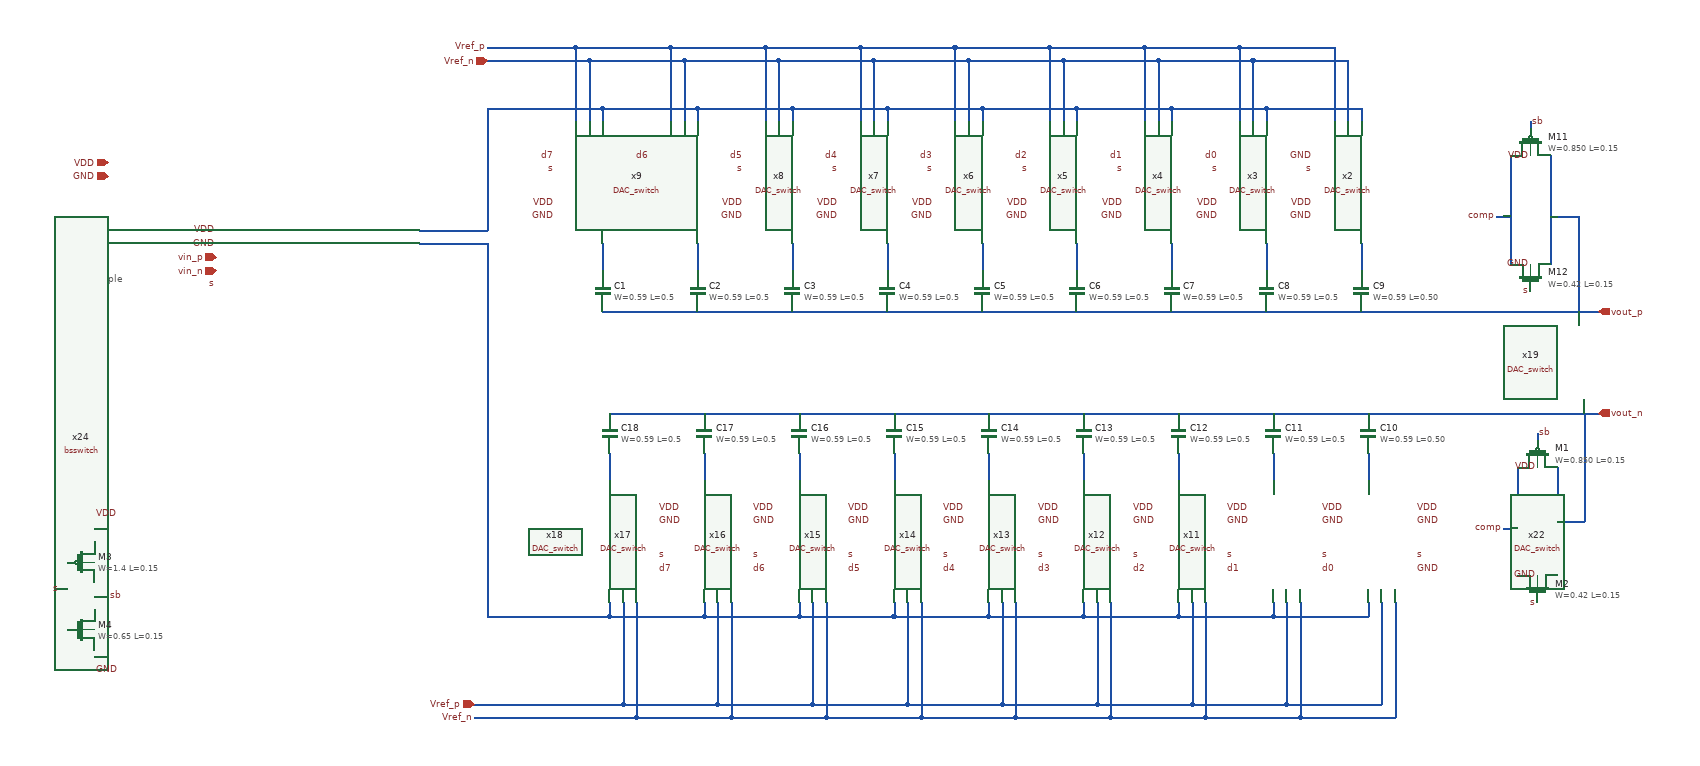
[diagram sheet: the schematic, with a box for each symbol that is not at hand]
v {xschem version=3.4.5 file_version=1.2
}
G {}
K {}
V {}
S {}
E {}
T {sample} -910 -60 0 0 0.2 0.2 {}
N -150 -300 -10 -300 {
lab=#net1}
N 830 -300 970 -300 {
lab=#net1}
N -10 -300 -10 -280 {
lab=#net1}
N 0 450 140 450 {
lab=#net2}
N 840 450 980 450 {
lab=#net2}
N -190 -390 -50 -390 {
lab=Vref_p}
N 880 600 1020 600 {
lab=Vref_n}
N -150 0 1080 0 {
lab=vout_p}
N -140 150 1160 150 {
lab=vout_n}
N 1080 0 1240 -0 {
lab=vout_p}
N 1160 150 1240 150 {
lab=vout_n}
N 1240 -0 1320 -0 {
lab=vout_p}
N 1240 150 1320 150 {
lab=vout_n}
N -420 -100 -320 -100 {
lab=#net1}
N -420 -120 -340 -120 {
lab=#net2}
N 950 -370 950 -290 {
lab=Vref_n}
N 930 -390 930 -280 {
lab=Vref_p}
N 790 -390 930 -390 {
lab=Vref_p}
N 790 -390 790 -280 {
lab=Vref_p}
N 810 -370 810 -280 {
lab=Vref_n}
N 650 -390 650 -280 {
lab=Vref_p}
N 670 -370 670 -280 {
lab=Vref_n}
N 510 -390 510 -280 {
lab=Vref_p}
N 530 -370 530 -280 {
lab=Vref_n}
N 370 -390 370 -280 {
lab=Vref_p}
N 390 -370 390 -280 {
lab=Vref_n}
N 230 -390 230 -280 {
lab=Vref_p}
N 250 -370 250 -280 {
lab=Vref_n}
N 90 -390 90 -280 {
lab=Vref_p}
N 110 -370 110 -280 {
lab=Vref_n}
N -50 -390 -50 -280 {
lab=Vref_p}
N -30 -370 -30 -280 {
lab=Vref_n}
N -190 -390 -190 -280 {
lab=Vref_p}
N -170 -370 -170 -280 {
lab=Vref_n}
N 810 -370 950 -370 {
lab=Vref_n}
N 1020 430 1020 600 {
lab=Vref_n}
N 1000 430 1000 580 {
lab=Vref_p}
N 880 430 880 600 {
lab=Vref_n}
N 860 430 860 580 {
lab=Vref_p}
N 740 430 740 600 {
lab=Vref_n}
N 720 430 720 580 {
lab=Vref_p}
N 600 430 600 600 {
lab=Vref_n}
N 580 430 580 580 {
lab=Vref_p}
N 460 430 460 600 {
lab=Vref_n}
N 440 430 440 580 {
lab=Vref_p}
N 320 430 320 600 {
lab=Vref_n}
N 300 430 300 580 {
lab=Vref_p}
N 180 430 180 600 {
lab=Vref_n}
N 160 430 160 580 {
lab=Vref_p}
N 40 430 40 600 {
lab=Vref_n}
N 20 430 20 580 {
lab=Vref_p}
N -100 430 -100 600 {
lab=Vref_n}
N -120 430 -120 580 {
lab=Vref_p}
N 860 580 1000 580 {
lab=Vref_p}
N 970 -300 970 -280 {
lab=#net1}
N 830 -300 830 -280 {
lab=#net1}
N 690 -300 690 -280 {
lab=#net1}
N 550 -300 550 -280 {
lab=#net1}
N 410 -300 410 -280 {
lab=#net1}
N 270 -300 270 -280 {
lab=#net1}
N 130 -300 130 -280 {
lab=#net1}
N -150 -300 -150 -280 {
lab=#net1}
N -140 210 -140 250 {
lab=#net3}
N 0 210 0 250 {
lab=#net4}
N 140 210 140 250 {
lab=#net5}
N 280 210 280 250 {
lab=#net6}
N 420 210 420 250 {
lab=#net7}
N 560 210 560 250 {
lab=#net8}
N 700 210 700 250 {
lab=#net9}
N 840 210 840 250 {
lab=#net10}
N 980 210 980 250 {
lab=#net11}
N -140 450 0 450 {
lab=#net2}
N 140 450 280 450 {
lab=#net2}
N 280 450 420 450 {
lab=#net2}
N 420 450 560 450 {
lab=#net2}
N 560 450 700 450 {
lab=#net2}
N 700 450 840 450 {
lab=#net2}
N 650 -390 790 -390 {
lab=Vref_p}
N 670 -370 810 -370 {
lab=Vref_n}
N 510 -390 650 -390 {
lab=Vref_p}
N 530 -370 670 -370 {
lab=Vref_n}
N 370 -390 510 -390 {
lab=Vref_p}
N 390 -370 530 -370 {
lab=Vref_n}
N 230 -390 370 -390 {
lab=Vref_p}
N 250 -370 390 -370 {
lab=Vref_n}
N 90 -390 230 -390 {
lab=Vref_p}
N 110 -370 250 -370 {
lab=Vref_n}
N -50 -390 90 -390 {
lab=Vref_p}
N -30 -370 110 -370 {
lab=Vref_n}
N -170 -370 -30 -370 {
lab=Vref_n}
N -320 -390 -190 -390 {
lab=Vref_p}
N -320 -370 -170 -370 {
lab=Vref_n}
N 740 600 880 600 {
lab=Vref_n}
N 720 580 860 580 {
lab=Vref_p}
N 600 600 740 600 {
lab=Vref_n}
N 580 580 720 580 {
lab=Vref_p}
N 460 600 600 600 {
lab=Vref_n}
N 440 580 580 580 {
lab=Vref_p}
N 320 600 460 600 {
lab=Vref_n}
N 300 580 440 580 {
lab=Vref_p}
N 180 600 320 600 {
lab=Vref_n}
N 160 580 300 580 {
lab=Vref_p}
N 40 600 180 600 {
lab=Vref_n}
N 20 580 160 580 {
lab=Vref_p}
N -100 600 40 600 {
lab=Vref_n}
N -120 580 20 580 {
lab=Vref_p}
N -340 600 -100 600 {
lab=Vref_n}
N -340 580 -120 580 {
lab=Vref_p}
N 690 -300 830 -300 {
lab=#net1}
N 550 -300 690 -300 {
lab=#net1}
N 410 -300 550 -300 {
lab=#net1}
N 270 -300 410 -300 {
lab=#net1}
N 130 -300 270 -300 {
lab=#net1}
N -10 -300 130 -300 {
lab=#net1}
N -320 -300 -150 -300 {
lab=#net1}
N 970 -100 970 -60 {
lab=#net12}
N 830 -100 830 -60 {
lab=#net13}
N 690 -100 690 -60 {
lab=#net14}
N 270 -100 270 -60 {
lab=#net18}
N 410 -100 410 -60 {
lab=#net19}
N 550 -100 550 -60 {
lab=#net20}
N 950 -290 950 -280 {
lab=Vref_n}
N 140 430 140 450 {
lab=#net2}
N 0 430 -0 450 {
lab=#net2}
N -140 430 -140 450 {
lab=#net2}
N 420 430 420 450 {
lab=#net2}
N 280 430 280 450 {
lab=#net2}
N 560 430 560 450 {
lab=#net2}
N 700 430 700 450 {
lab=#net2}
N 840 430 840 450 {
lab=#net2}
N 980 430 980 450 {
lab=#net2}
N 1190 -230 1190 -70 {
lab=comp}
N 1250 -230 1250 -70 {
lab=vout_p}
N 1170 -140 1190 -140 {
lab=comp}
N 1250 -140 1290 -140 {
lab=vout_p}
N 1220 -280 1220 -270 {
lab=sb}
N 1290 -140 1290 0 {
lab=vout_p}
N -900 400 -900 440 {
lab=sb}
N -940 370 -940 470 {
lab=s}
N -900 500 -900 530 {
lab=GND}
N -900 300 -900 340 {
lab=VDD}
N -900 370 -890 370 {
lab=VDD}
N -890 320 -890 370 {
lab=VDD}
N -900 320 -890 320 {
lab=VDD}
N -900 470 -890 470 {
lab=GND}
N -890 470 -890 510 {
lab=GND}
N -900 510 -890 510 {
lab=GND}
N -950 410 -940 410 {
lab=s}
N -900 420 -880 420 {
lab=sb}
N 1200 230 1200 390 {
lab=comp}
N 1260 230 1260 390 {
lab=vout_n}
N 1180 320 1200 320 {
lab=comp}
N 1230 180 1230 190 {
lab=sb}
N 1260 310 1300 310 {
lab=vout_n}
N 1300 150 1300 310 {
lab=vout_n}
N -340 -120 -320 -120 {}
N -320 -300 -320 -120 {}
N -320 -100 -320 450 {}
N -320 450 -140 450 {}
N 130 -100 130 -60 {}
N -150 -100 -150 -60 {}
N -10 -100 -10 -60 {}
C {sky130_fd_pr/cap_mim_m3_1.sym} -150 -30 2 0 {name=C1 model=cap_mim_m3_1 W=0.59 L=0.5 MF=128 spiceprefix=X}
C {sky130_fd_pr/cap_mim_m3_1.sym} -10 -30 2 0 {name=C2 model=cap_mim_m3_1 W=0.59 L=0.5 MF=64 spiceprefix=X}
C {sky130_fd_pr/cap_mim_m3_1.sym} 130 -30 2 0 {name=C3 model=cap_mim_m3_1 W=0.59 L=0.5 MF=32 spiceprefix=X}
C {sky130_fd_pr/cap_mim_m3_1.sym} 270 -30 2 0 {name=C4 model=cap_mim_m3_1 W=0.59 L=0.5 MF=16 spiceprefix=X}
C {sky130_fd_pr/cap_mim_m3_1.sym} 410 -30 2 0 {name=C5 model=cap_mim_m3_1 W=0.59 L=0.5 MF=8 spiceprefix=X}
C {sky130_fd_pr/cap_mim_m3_1.sym} 550 -30 2 0 {name=C6 model=cap_mim_m3_1 W=0.59 L=0.5 MF=4 spiceprefix=X}
C {sky130_fd_pr/cap_mim_m3_1.sym} 690 -30 2 0 {name=C7 model=cap_mim_m3_1 W=0.59 L=0.5 MF=2 spiceprefix=X}
C {sky130_fd_pr/cap_mim_m3_1.sym} 830 -30 2 0 {name=C8 model=cap_mim_m3_1 W=0.59 L=0.5 MF=1 spiceprefix=X}
C {sky130_fd_pr/cap_mim_m3_1.sym} 970 -30 2 0 {name=C9 model=cap_mim_m3_1 W=0.59 L=0.50 MF=1 spiceprefix=X}
C {devices/lab_pin.sym} -720 -120 0 0 {name=p2 sig_type=std_logic lab=VDD}
C {devices/lab_pin.sym} -720 -100 0 0 {name=p9 sig_type=std_logic lab=GND}
C {devices/lab_pin.sym} -220 -160 0 0 {name=p1 sig_type=std_logic lab=VDD}
C {devices/lab_pin.sym} -220 -140 0 0 {name=p3 sig_type=std_logic lab=GND}
C {devices/lab_pin.sym} -80 -160 0 0 {name=p4 sig_type=std_logic lab=VDD}
C {devices/lab_pin.sym} -80 -140 0 0 {name=p5 sig_type=std_logic lab=GND}
C {devices/lab_pin.sym} 60 -160 0 0 {name=p6 sig_type=std_logic lab=VDD}
C {devices/lab_pin.sym} 60 -140 0 0 {name=p7 sig_type=std_logic lab=GND}
C {devices/lab_pin.sym} 200 -160 0 0 {name=p8 sig_type=std_logic lab=VDD}
C {devices/lab_pin.sym} 200 -140 0 0 {name=p10 sig_type=std_logic lab=GND}
C {devices/lab_pin.sym} 340 -160 0 0 {name=p11 sig_type=std_logic lab=VDD}
C {devices/lab_pin.sym} 340 -140 0 0 {name=p12 sig_type=std_logic lab=GND}
C {devices/lab_pin.sym} 480 -160 0 0 {name=p13 sig_type=std_logic lab=VDD}
C {devices/lab_pin.sym} 480 -140 0 0 {name=p14 sig_type=std_logic lab=GND}
C {devices/lab_pin.sym} 620 -160 0 0 {name=p15 sig_type=std_logic lab=VDD}
C {devices/lab_pin.sym} 620 -140 0 0 {name=p16 sig_type=std_logic lab=GND}
C {devices/lab_pin.sym} 760 -160 0 0 {name=p17 sig_type=std_logic lab=VDD}
C {devices/lab_pin.sym} 760 -140 0 0 {name=p18 sig_type=std_logic lab=GND}
C {devices/lab_pin.sym} 900 -160 0 0 {name=p19 sig_type=std_logic lab=VDD}
C {devices/lab_pin.sym} 900 -140 0 0 {name=p20 sig_type=std_logic lab=GND}
C {devices/lab_pin.sym} -70 290 0 1 {name=p21 sig_type=std_logic lab=VDD}
C {devices/lab_pin.sym} -70 310 0 1 {name=p22 sig_type=std_logic lab=GND}
C {devices/lab_pin.sym} 70 290 0 1 {name=p23 sig_type=std_logic lab=VDD}
C {devices/lab_pin.sym} 70 310 0 1 {name=p24 sig_type=std_logic lab=GND}
C {devices/lab_pin.sym} 210 290 0 1 {name=p25 sig_type=std_logic lab=VDD}
C {devices/lab_pin.sym} 210 310 0 1 {name=p26 sig_type=std_logic lab=GND}
C {devices/lab_pin.sym} 350 290 0 1 {name=p27 sig_type=std_logic lab=VDD}
C {devices/lab_pin.sym} 350 310 0 1 {name=p28 sig_type=std_logic lab=GND}
C {devices/lab_pin.sym} 490 290 0 1 {name=p29 sig_type=std_logic lab=VDD}
C {devices/lab_pin.sym} 490 310 0 1 {name=p30 sig_type=std_logic lab=GND}
C {devices/lab_pin.sym} 630 290 0 1 {name=p31 sig_type=std_logic lab=VDD}
C {devices/lab_pin.sym} 630 310 0 1 {name=p32 sig_type=std_logic lab=GND}
C {devices/lab_pin.sym} 770 290 0 1 {name=p33 sig_type=std_logic lab=VDD}
C {devices/lab_pin.sym} 770 310 0 1 {name=p34 sig_type=std_logic lab=GND}
C {devices/lab_pin.sym} 910 290 0 1 {name=p35 sig_type=std_logic lab=VDD}
C {devices/lab_pin.sym} 910 310 0 1 {name=p36 sig_type=std_logic lab=GND}
C {devices/lab_pin.sym} 1050 290 0 1 {name=p37 sig_type=std_logic lab=VDD}
C {devices/lab_pin.sym} 1050 310 0 1 {name=p38 sig_type=std_logic lab=GND}
C {devices/ipin.sym} -320 -370 0 0 {name=p39 lab=Vref_n}
C {devices/ipin.sym} -880 20 0 0 {name=p40 lab=d0
}
C {devices/lab_pin.sym} -320 -390 0 0 {name=p41 sig_type=std_logic lab=Vref_p}
C {devices/ipin.sym} -340 580 0 0 {name=p44 lab=Vref_p}
C {devices/lab_pin.sym} -340 600 0 0 {name=p45 sig_type=std_logic lab=Vref_n}
C {devices/ipin.sym} -880 50 0 0 {name=p46 lab=d1
}
C {devices/ipin.sym} -880 80 0 0 {name=p47 lab=d2
}
C {devices/ipin.sym} -880 110 0 0 {name=p48 lab=d3
}
C {devices/ipin.sym} -880 140 0 0 {name=p49 lab=d4
}
C {devices/ipin.sym} -880 170 0 0 {name=p50 lab=d5
}
C {devices/ipin.sym} -880 200 0 0 {name=p51 lab=d6
}
C {devices/ipin.sym} -880 230 0 0 {name=p52 lab=d7
}
C {devices/lab_pin.sym} -220 -230 0 0 {name=p53 sig_type=std_logic lab=d7}
C {devices/lab_pin.sym} 60 -230 0 0 {name=p55 sig_type=std_logic lab=d5}
C {devices/lab_pin.sym} 200 -230 0 0 {name=p56 sig_type=std_logic lab=d4}
C {devices/lab_pin.sym} 340 -230 0 0 {name=p57 sig_type=std_logic lab=d3}
C {devices/lab_pin.sym} 480 -230 0 0 {name=p58 sig_type=std_logic lab=d2}
C {devices/lab_pin.sym} 620 -230 0 0 {name=p59 sig_type=std_logic lab=d1}
C {devices/lab_pin.sym} 760 -230 0 0 {name=p60 sig_type=std_logic lab=d0}
C {devices/lab_pin.sym} -70 380 0 1 {name=p62 sig_type=std_logic lab=d7}
C {devices/lab_pin.sym} 70 380 0 1 {name=p63 sig_type=std_logic lab=d6}
C {devices/lab_pin.sym} 210 380 0 1 {name=p64 sig_type=std_logic lab=d5}
C {devices/lab_pin.sym} 350 380 0 1 {name=p65 sig_type=std_logic lab=d4}
C {devices/lab_pin.sym} 490 380 0 1 {name=p66 sig_type=std_logic lab=d3}
C {devices/lab_pin.sym} 630 380 0 1 {name=p67 sig_type=std_logic lab=d2}
C {devices/lab_pin.sym} 770 380 0 1 {name=p68 sig_type=std_logic lab=d1}
C {devices/lab_pin.sym} 910 380 0 1 {name=p69 sig_type=std_logic lab=d0}
C {devices/ipin.sym} -880 -40 0 0 {name=p71 lab=s
}
C {devices/lab_pin.sym} -220 -210 0 0 {name=p72 sig_type=std_logic lab=s}
C {devices/lab_pin.sym} -80 -210 0 0 {name=p73 sig_type=std_logic lab=s}
C {devices/lab_pin.sym} 60 -210 0 0 {name=p74 sig_type=std_logic lab=s}
C {devices/lab_pin.sym} 200 -210 0 0 {name=p75 sig_type=std_logic lab=s}
C {devices/lab_pin.sym} 340 -210 0 0 {name=p76 sig_type=std_logic lab=s}
C {devices/lab_pin.sym} 480 -210 0 0 {name=p77 sig_type=std_logic lab=s}
C {devices/lab_pin.sym} 620 -210 0 0 {name=p78 sig_type=std_logic lab=s}
C {devices/lab_pin.sym} 760 -210 0 0 {name=p79 sig_type=std_logic lab=s}
C {devices/lab_pin.sym} 900 -210 0 0 {name=p80 sig_type=std_logic lab=s}
C {devices/lab_pin.sym} -70 360 0 1 {name=p81 sig_type=std_logic lab=s}
C {devices/lab_pin.sym} 70 360 0 1 {name=p82 sig_type=std_logic lab=s}
C {devices/lab_pin.sym} 210 360 0 1 {name=p83 sig_type=std_logic lab=s}
C {devices/lab_pin.sym} 350 360 0 1 {name=p84 sig_type=std_logic lab=s}
C {devices/lab_pin.sym} 490 360 0 1 {name=p85 sig_type=std_logic lab=s}
C {devices/lab_pin.sym} 630 360 0 1 {name=p86 sig_type=std_logic lab=s}
C {devices/lab_pin.sym} 770 360 0 1 {name=p87 sig_type=std_logic lab=s}
C {devices/lab_pin.sym} 910 360 0 1 {name=p88 sig_type=std_logic lab=s}
C {devices/lab_pin.sym} 1050 360 0 1 {name=p89 sig_type=std_logic lab=s}
C {devices/ipin.sym} -880 -80 0 0 {name=p94 lab=comp
}
C {devices/opin.sym} 1320 0 0 0 {name=p101 lab=vout_p}
C {devices/opin.sym} 1320 150 0 0 {name=p102 lab=vout_n}
C {devices/lab_pin.sym} -720 -40 0 0 {name=p104 sig_type=std_logic lab=s}
C {devices/ipin.sym} -720 -60 0 0 {name=p105 lab=vin_n
}
C {devices/ipin.sym} -720 -80 0 0 {name=p106 lab=vin_p
}
C {devices/ipin.sym} -880 -220 0 0 {name=p107 lab=VDD
}
C {devices/ipin.sym} -880 -200 0 0 {name=p108 lab=GND
}
C {bsswitch.sym} -570 -80 0 0 {name=x24}
C {devices/lab_pin.sym} 1170 -140 0 0 {name=p95 sig_type=std_logic lab=comp}
C {devices/lab_pin.sym} 900 -230 0 0 {name=p61 sig_type=std_logic lab=GND}
C {devices/lab_pin.sym} 1050 380 0 1 {name=p70 sig_type=std_logic lab=GND}
C {DAC_switch.sym} 900 340 2 0 {name=x22}
C {DAC_switch.sym} 760 340 2 0 {name=x11}
C {DAC_switch.sym} 620 340 2 0 {name=x12}
C {DAC_switch.sym} 480 340 2 0 {name=x13}
C {DAC_switch.sym} 340 340 2 0 {name=x14}
C {DAC_switch.sym} 200 340 2 0 {name=x15}
C {DAC_switch.sym} 60 340 2 0 {name=x16}
C {DAC_switch.sym} -80 340 2 0 {name=x17}
C {DAC_switch.sym} -220 340 2 0 {name=x18}
C {DAC_switch.sym} 1050 -190 0 0 {name=x19}
C {DAC_switch.sym} 910 -190 0 0 {name=x2}
C {DAC_switch.sym} 770 -190 0 0 {name=x3}
C {DAC_switch.sym} 630 -190 0 0 {name=x4}
C {DAC_switch.sym} 490 -190 0 0 {name=x5}
C {DAC_switch.sym} 350 -190 0 0 {name=x6}
C {DAC_switch.sym} 210 -190 0 0 {name=x7}
C {DAC_switch.sym} 70 -190 0 0 {name=x8}
C {DAC_switch.sym} -70 -190 0 0 {name=x9}
C {sky130_fd_pr/pfet_01v8.sym} 1220 -250 1 0 {name=M11
L=0.15
W=0.850
nf=1
mult=1
ad="'int((nf+1)/2) * W/nf * 0.29'" 
pd="'2*int((nf+1)/2) * (W/nf + 0.29)'"
as="'int((nf+2)/2) * W/nf * 0.29'" 
ps="'2*int((nf+2)/2) * (W/nf + 0.29)'"
nrd="'0.29 / W'" nrs="'0.29 / W'"
sa=0 sb=0 sd=0
model=pfet_01v8
spiceprefix=X
}
C {sky130_fd_pr/nfet_01v8.sym} 1220 -50 3 0 {name=M12
L=0.15
W=0.42
nf=1 
mult=1
ad="'int((nf+1)/2) * W/nf * 0.29'" 
pd="'2*int((nf+1)/2) * (W/nf + 0.29)'"
as="'int((nf+2)/2) * W/nf * 0.29'" 
ps="'2*int((nf+2)/2) * (W/nf + 0.29)'"
nrd="'0.29 / W'" nrs="'0.29 / W'"
sa=0 sb=0 sd=0
model=nfet_01v8
spiceprefix=X
}
C {devices/lab_pin.sym} 1220 -30 0 0 {name=p43 sig_type=std_logic lab=s}
C {devices/lab_pin.sym} 1220 -230 3 0 {name=p91 sig_type=std_logic lab=VDD}
C {devices/lab_pin.sym} 1220 -70 1 0 {name=p92 sig_type=std_logic lab=GND
}
C {devices/lab_pin.sym} -950 410 0 0 {name=p42 sig_type=std_logic lab=s}
C {devices/lab_pin.sym} -880 420 0 1 {name=p98 sig_type=std_logic lab=sb}
C {sky130_fd_pr/pfet_01v8.sym} -920 370 0 0 {name=M3
L=0.15
W=1.4
nf=1
mult=1
ad="'int((nf+1)/2) * W/nf * 0.29'" 
pd="'2*int((nf+1)/2) * (W/nf + 0.29)'"
as="'int((nf+2)/2) * W/nf * 0.29'" 
ps="'2*int((nf+2)/2) * (W/nf + 0.29)'"
nrd="'0.29 / W'" nrs="'0.29 / W'"
sa=0 sb=0 sd=0
model=pfet_01v8
spiceprefix=X
}
C {sky130_fd_pr/nfet_01v8.sym} -920 470 0 0 {name=M4
L=0.15
W=0.65
nf=1 
mult=1
ad="'int((nf+1)/2) * W/nf * 0.29'" 
pd="'2*int((nf+1)/2) * (W/nf + 0.29)'"
as="'int((nf+2)/2) * W/nf * 0.29'" 
ps="'2*int((nf+2)/2) * (W/nf + 0.29)'"
nrd="'0.29 / W'" nrs="'0.29 / W'"
sa=0 sb=0 sd=0
model=nfet_01v8
spiceprefix=X
}
C {devices/lab_pin.sym} -900 300 2 0 {name=p100 sig_type=std_logic lab=VDD}
C {devices/lab_pin.sym} -900 530 2 0 {name=p103 sig_type=std_logic lab=GND
}
C {devices/lab_pin.sym} 1220 -280 0 1 {name=p97 sig_type=std_logic lab=sb}
C {devices/lab_pin.sym} 1180 320 0 0 {name=p90 sig_type=std_logic lab=comp}
C {sky130_fd_pr/pfet_01v8.sym} 1230 210 1 0 {name=M1
L=0.15
W=0.850
nf=1
mult=1
ad="'int((nf+1)/2) * W/nf * 0.29'" 
pd="'2*int((nf+1)/2) * (W/nf + 0.29)'"
as="'int((nf+2)/2) * W/nf * 0.29'" 
ps="'2*int((nf+2)/2) * (W/nf + 0.29)'"
nrd="'0.29 / W'" nrs="'0.29 / W'"
sa=0 sb=0 sd=0
model=pfet_01v8
spiceprefix=X
}
C {sky130_fd_pr/nfet_01v8.sym} 1230 410 3 0 {name=M2
L=0.15
W=0.42
nf=1 
mult=1
ad="'int((nf+1)/2) * W/nf * 0.29'" 
pd="'2*int((nf+1)/2) * (W/nf + 0.29)'"
as="'int((nf+2)/2) * W/nf * 0.29'" 
ps="'2*int((nf+2)/2) * (W/nf + 0.29)'"
nrd="'0.29 / W'" nrs="'0.29 / W'"
sa=0 sb=0 sd=0
model=nfet_01v8
spiceprefix=X
}
C {devices/lab_pin.sym} 1230 430 0 0 {name=p93 sig_type=std_logic lab=s}
C {devices/lab_pin.sym} 1230 230 3 0 {name=p99 sig_type=std_logic lab=VDD}
C {devices/lab_pin.sym} 1230 390 1 0 {name=p109 sig_type=std_logic lab=GND
}
C {devices/lab_pin.sym} 1230 180 0 1 {name=p110 sig_type=std_logic lab=sb}
C {sky130_fd_pr/cap_mim_m3_1.sym} 980 180 0 0 {name=C10 model=cap_mim_m3_1 W=0.59 L=0.50 MF=1 spiceprefix=X}
C {sky130_fd_pr/cap_mim_m3_1.sym} 840 180 0 0 {name=C11 model=cap_mim_m3_1 W=0.59 L=0.5 MF=1 spiceprefix=X}
C {sky130_fd_pr/cap_mim_m3_1.sym} 700 180 0 0 {name=C12 model=cap_mim_m3_1 W=0.59 L=0.5 MF=2 spiceprefix=X}
C {sky130_fd_pr/cap_mim_m3_1.sym} 560 180 0 0 {name=C13 model=cap_mim_m3_1 W=0.59 L=0.5 MF=4 spiceprefix=X}
C {sky130_fd_pr/cap_mim_m3_1.sym} 420 180 0 0 {name=C14 model=cap_mim_m3_1 W=0.59 L=0.5 MF=8 spiceprefix=X}
C {sky130_fd_pr/cap_mim_m3_1.sym} 280 180 0 0 {name=C15 model=cap_mim_m3_1 W=0.59 L=0.5 MF=16 spiceprefix=X}
C {sky130_fd_pr/cap_mim_m3_1.sym} 140 180 0 0 {name=C16 model=cap_mim_m3_1 W=0.59 L=0.5 MF=32 spiceprefix=X}
C {sky130_fd_pr/cap_mim_m3_1.sym} 0 180 0 0 {name=C17 model=cap_mim_m3_1 W=0.59 L=0.5 MF=64 spiceprefix=X}
C {sky130_fd_pr/cap_mim_m3_1.sym} -140 180 0 0 {name=C18 model=cap_mim_m3_1 W=0.59 L=0.5 MF=128 spiceprefix=X}
C {devices/lab_pin.sym} -80 -230 2 1 {name=p54 sig_type=std_logic lab=d6}
